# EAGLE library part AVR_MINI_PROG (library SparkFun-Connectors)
AVR ISP 6-pin inline header

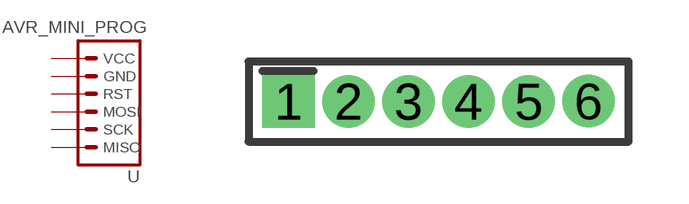
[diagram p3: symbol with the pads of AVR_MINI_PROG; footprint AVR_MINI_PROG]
Designator prefix -

## AVR_MINI_PROGSMD  [AVR_MINI_PROG]
1  VCC  pas
2  GND  pas
3  RST  pas
4  MOSI  pas
5  SCK  pas
6  MISO  pas

## Footprint AVR_MINI_PROG (pad centres in mm)
drill 0.8 pad 1.27 square: 1 0,0
drill 0.8 pad 1.27: 2 1.5,0; 3 3,0; 4 4.5,0; 5 6,0; 6 7.5,0.01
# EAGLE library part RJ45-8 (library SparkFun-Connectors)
RJ45 Jack Simple RJ45, 8-pin connection - connector for common Cat5, Cat5e, and Cat6 Ethernet cables. Footprint not yet proven in production. Connector sku is PRT-00643; Breakout PCB sku is BOB-00716.

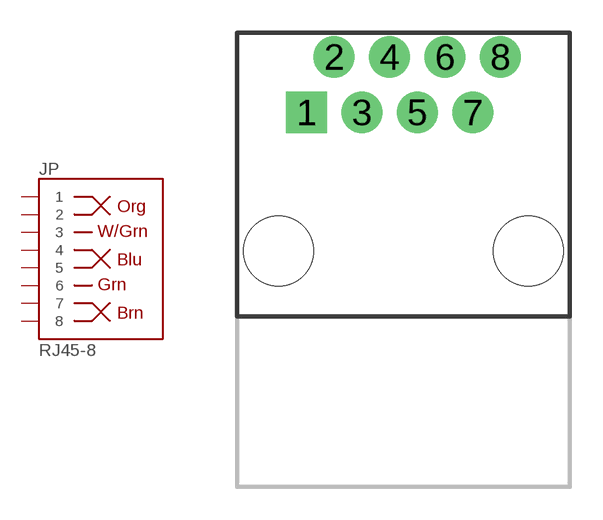
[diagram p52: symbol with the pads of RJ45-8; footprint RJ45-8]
Designator prefix JP

## RJ45-8PTH (PROD_ID: CONN-08506; VALUE: RJ45)  [RJ45-8]
1  1
2  2
3  3
4  4
5  5
6  6
7  7
8  8

## Footprint RJ45-8 (pad centres in mm)
drill 1 pad 1.88 square: 1 -4.445,6.35
drill 1 pad 1.88: 2 -3.175,8.89; 3 -1.905,6.35; 4 -0.635,8.89; 5 0.635,6.35; 6 1.905,8.89; 7 3.175,6.35; 8 4.445,8.89
hole 3.2 at -5.715,0
hole 3.2 at 5.715,0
